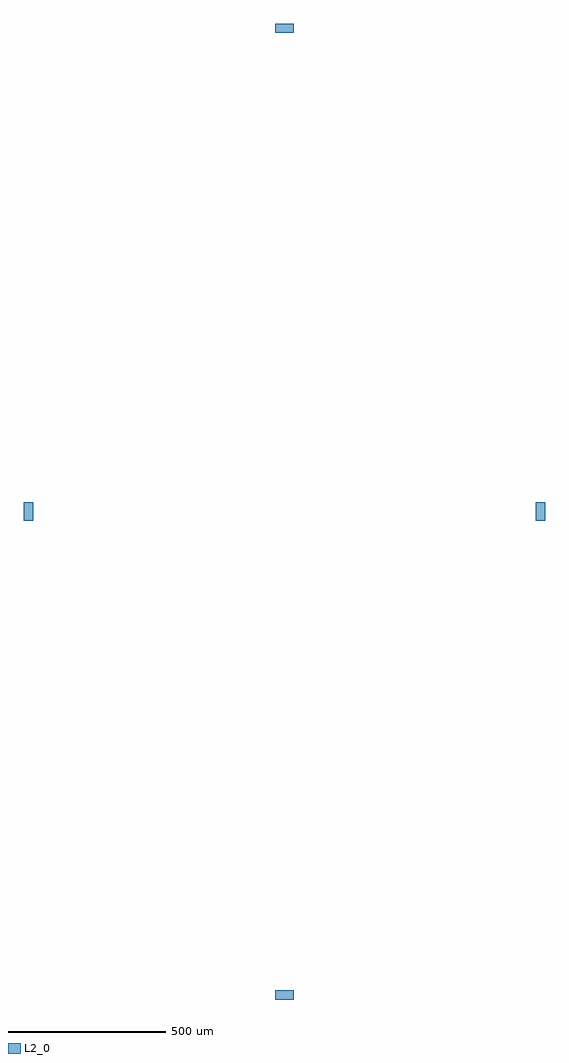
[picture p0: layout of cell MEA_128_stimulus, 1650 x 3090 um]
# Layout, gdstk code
import gdstk
lib = gdstk.Library(unit=1e-6, precision=1e-09)
def R(c, l, rs):  # rectangles x0, y0, x1, y1
    for r in rs: c.add(gdstk.rectangle(r[:2], r[2:], *l))
L2_0 = (2, 0)

mea_128_stimulus = lib.new_cell('MEA_128_stimulus')
R(mea_128_stimulus, L2_0, [(-30,-1545,30,-1515), (-30,-1545,30,-1515), (-30,-1545,30,-1515), (-825,-30,-795,30), (-825,-30,-795,30), (-825,-30,-795,30), (-825,-30,-795,30), (-825,-30,-795,30), (-825,-30,-795,30), (795,-30,825,30), (795,-30,825,30), (795,-30,825,30), (795,-30,825,30), (795,-30,825,30), (795,-30,825,30), (-30,1515,30,1545), (-30,1515,30,1545), (-30,1515,30,1545)])

lib.write_gds('MEA_128_stimulus.gds')
